VERSION 5.7 ;
BUSBITCHARS "[]" ;
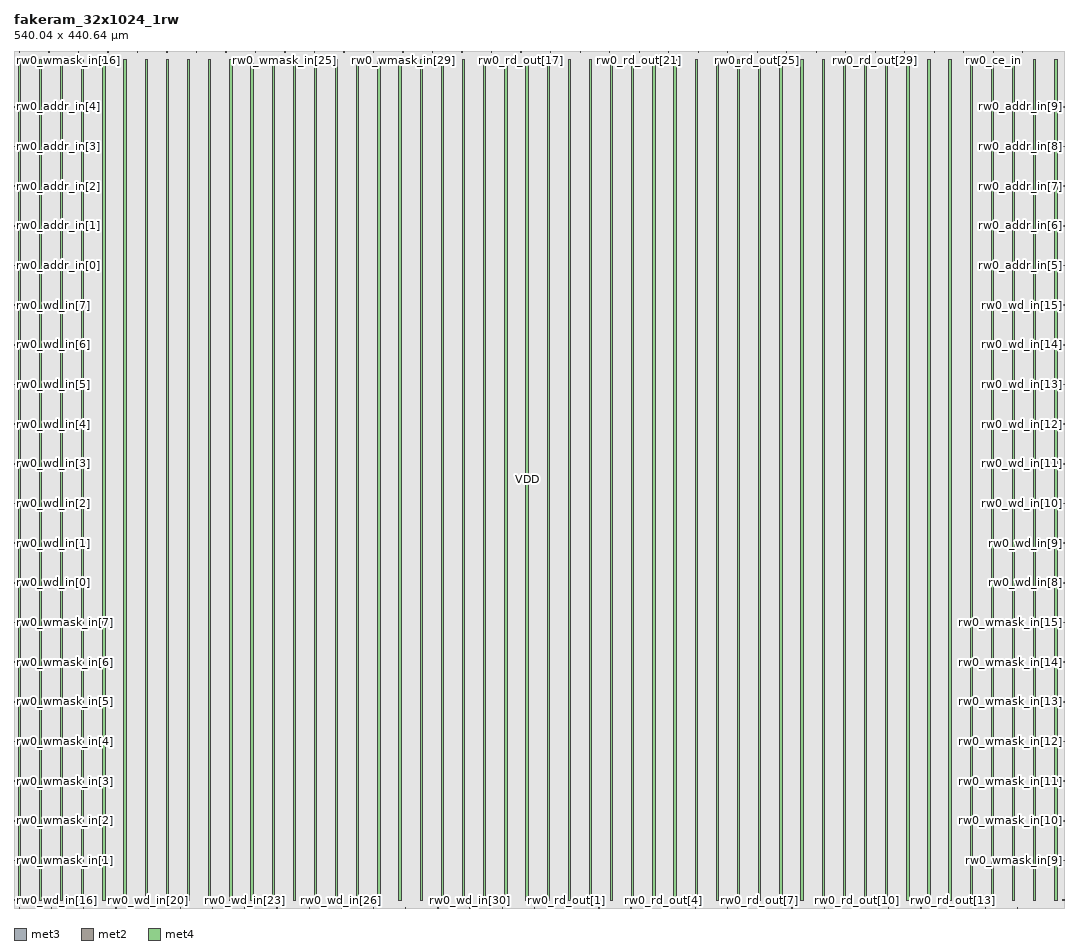
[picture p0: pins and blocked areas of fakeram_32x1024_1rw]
MACRO fakeram_32x1024_1rw
  FOREIGN fakeram_32x1024_1rw 0 0 ;
  SYMMETRY X Y R90 ;
  SIZE 540.040 BY 440.640 ;
  CLASS BLOCK ;
  PIN rw0_wmask_in[0]
    DIRECTION INPUT ;
    USE SIGNAL ;
    SHAPE ABUTMENT ;
    PORT
      LAYER met3 ;
      RECT 0.000 3.930 0.900 4.230 ;
    END
  END rw0_wmask_in[0]
  PIN rw0_wmask_in[1]
    DIRECTION INPUT ;
    USE SIGNAL ;
    SHAPE ABUTMENT ;
    PORT
      LAYER met3 ;
      RECT 0.000 24.330 0.900 24.630 ;
    END
  END rw0_wmask_in[1]
  PIN rw0_wmask_in[2]
    DIRECTION INPUT ;
    USE SIGNAL ;
    SHAPE ABUTMENT ;
    PORT
      LAYER met3 ;
      RECT 0.000 44.730 0.900 45.030 ;
    END
  END rw0_wmask_in[2]
  PIN rw0_wmask_in[3]
    DIRECTION INPUT ;
    USE SIGNAL ;
    SHAPE ABUTMENT ;
    PORT
      LAYER met3 ;
      RECT 0.000 65.130 0.900 65.430 ;
    END
  END rw0_wmask_in[3]
  PIN rw0_wmask_in[4]
    DIRECTION INPUT ;
    USE SIGNAL ;
    SHAPE ABUTMENT ;
    PORT
      LAYER met3 ;
      RECT 0.000 85.530 0.900 85.830 ;
    END
  END rw0_wmask_in[4]
  PIN rw0_wmask_in[5]
    DIRECTION INPUT ;
    USE SIGNAL ;
    SHAPE ABUTMENT ;
    PORT
      LAYER met3 ;
      RECT 0.000 105.930 0.900 106.230 ;
    END
  END rw0_wmask_in[5]
  PIN rw0_wmask_in[6]
    DIRECTION INPUT ;
    USE SIGNAL ;
    SHAPE ABUTMENT ;
    PORT
      LAYER met3 ;
      RECT 0.000 126.330 0.900 126.630 ;
    END
  END rw0_wmask_in[6]
  PIN rw0_wmask_in[7]
    DIRECTION INPUT ;
    USE SIGNAL ;
    SHAPE ABUTMENT ;
    PORT
      LAYER met3 ;
      RECT 0.000 146.730 0.900 147.030 ;
    END
  END rw0_wmask_in[7]
  PIN rw0_wmask_in[8]
    DIRECTION INPUT ;
    USE SIGNAL ;
    SHAPE ABUTMENT ;
    PORT
      LAYER met3 ;
      RECT 539.140 3.930 540.040 4.230 ;
    END
  END rw0_wmask_in[8]
  PIN rw0_wmask_in[9]
    DIRECTION INPUT ;
    USE SIGNAL ;
    SHAPE ABUTMENT ;
    PORT
      LAYER met3 ;
      RECT 539.140 24.330 540.040 24.630 ;
    END
  END rw0_wmask_in[9]
  PIN rw0_wmask_in[10]
    DIRECTION INPUT ;
    USE SIGNAL ;
    SHAPE ABUTMENT ;
    PORT
      LAYER met3 ;
      RECT 539.140 44.730 540.040 45.030 ;
    END
  END rw0_wmask_in[10]
  PIN rw0_wmask_in[11]
    DIRECTION INPUT ;
    USE SIGNAL ;
    SHAPE ABUTMENT ;
    PORT
      LAYER met3 ;
      RECT 539.140 65.130 540.040 65.430 ;
    END
  END rw0_wmask_in[11]
  PIN rw0_wmask_in[12]
    DIRECTION INPUT ;
    USE SIGNAL ;
    SHAPE ABUTMENT ;
    PORT
      LAYER met3 ;
      RECT 539.140 85.530 540.040 85.830 ;
    END
  END rw0_wmask_in[12]
  PIN rw0_wmask_in[13]
    DIRECTION INPUT ;
    USE SIGNAL ;
    SHAPE ABUTMENT ;
    PORT
      LAYER met3 ;
      RECT 539.140 105.930 540.040 106.230 ;
    END
  END rw0_wmask_in[13]
  PIN rw0_wmask_in[14]
    DIRECTION INPUT ;
    USE SIGNAL ;
    SHAPE ABUTMENT ;
    PORT
      LAYER met3 ;
      RECT 539.140 126.330 540.040 126.630 ;
    END
  END rw0_wmask_in[14]
  PIN rw0_wmask_in[15]
    DIRECTION INPUT ;
    USE SIGNAL ;
    SHAPE ABUTMENT ;
    PORT
      LAYER met3 ;
      RECT 539.140 146.730 540.040 147.030 ;
    END
  END rw0_wmask_in[15]
  PIN rw0_wmask_in[16]
    DIRECTION INPUT ;
    USE SIGNAL ;
    SHAPE ABUTMENT ;
    PORT
      LAYER met2 ;
      RECT 2.690 440.220 2.830 440.640 ;
    END
  END rw0_wmask_in[16]
  PIN rw0_wmask_in[17]
    DIRECTION INPUT ;
    USE SIGNAL ;
    SHAPE ABUTMENT ;
    PORT
      LAYER met2 ;
      RECT 17.870 440.220 18.010 440.640 ;
    END
  END rw0_wmask_in[17]
  PIN rw0_wmask_in[18]
    DIRECTION INPUT ;
    USE SIGNAL ;
    SHAPE ABUTMENT ;
    PORT
      LAYER met2 ;
      RECT 33.050 440.220 33.190 440.640 ;
    END
  END rw0_wmask_in[18]
  PIN rw0_wmask_in[19]
    DIRECTION INPUT ;
    USE SIGNAL ;
    SHAPE ABUTMENT ;
    PORT
      LAYER met2 ;
      RECT 48.230 440.220 48.370 440.640 ;
    END
  END rw0_wmask_in[19]
  PIN rw0_wmask_in[20]
    DIRECTION INPUT ;
    USE SIGNAL ;
    SHAPE ABUTMENT ;
    PORT
      LAYER met2 ;
      RECT 63.410 440.220 63.550 440.640 ;
    END
  END rw0_wmask_in[20]
  PIN rw0_wmask_in[21]
    DIRECTION INPUT ;
    USE SIGNAL ;
    SHAPE ABUTMENT ;
    PORT
      LAYER met2 ;
      RECT 78.590 440.220 78.730 440.640 ;
    END
  END rw0_wmask_in[21]
  PIN rw0_wmask_in[22]
    DIRECTION INPUT ;
    USE SIGNAL ;
    SHAPE ABUTMENT ;
    PORT
      LAYER met2 ;
      RECT 93.770 440.220 93.910 440.640 ;
    END
  END rw0_wmask_in[22]
  PIN rw0_wmask_in[23]
    DIRECTION INPUT ;
    USE SIGNAL ;
    SHAPE ABUTMENT ;
    PORT
      LAYER met2 ;
      RECT 108.950 440.220 109.090 440.640 ;
    END
  END rw0_wmask_in[23]
  PIN rw0_wmask_in[24]
    DIRECTION INPUT ;
    USE SIGNAL ;
    SHAPE ABUTMENT ;
    PORT
      LAYER met2 ;
      RECT 124.130 440.220 124.270 440.640 ;
    END
  END rw0_wmask_in[24]
  PIN rw0_wmask_in[25]
    DIRECTION INPUT ;
    USE SIGNAL ;
    SHAPE ABUTMENT ;
    PORT
      LAYER met2 ;
      RECT 139.310 440.220 139.450 440.640 ;
    END
  END rw0_wmask_in[25]
  PIN rw0_wmask_in[26]
    DIRECTION INPUT ;
    USE SIGNAL ;
    SHAPE ABUTMENT ;
    PORT
      LAYER met2 ;
      RECT 154.490 440.220 154.630 440.640 ;
    END
  END rw0_wmask_in[26]
  PIN rw0_wmask_in[27]
    DIRECTION INPUT ;
    USE SIGNAL ;
    SHAPE ABUTMENT ;
    PORT
      LAYER met2 ;
      RECT 169.670 440.220 169.810 440.640 ;
    END
  END rw0_wmask_in[27]
  PIN rw0_wmask_in[28]
    DIRECTION INPUT ;
    USE SIGNAL ;
    SHAPE ABUTMENT ;
    PORT
      LAYER met2 ;
      RECT 184.850 440.220 184.990 440.640 ;
    END
  END rw0_wmask_in[28]
  PIN rw0_wmask_in[29]
    DIRECTION INPUT ;
    USE SIGNAL ;
    SHAPE ABUTMENT ;
    PORT
      LAYER met2 ;
      RECT 200.030 440.220 200.170 440.640 ;
    END
  END rw0_wmask_in[29]
  PIN rw0_wmask_in[30]
    DIRECTION INPUT ;
    USE SIGNAL ;
    SHAPE ABUTMENT ;
    PORT
      LAYER met2 ;
      RECT 215.210 440.220 215.350 440.640 ;
    END
  END rw0_wmask_in[30]
  PIN rw0_wmask_in[31]
    DIRECTION INPUT ;
    USE SIGNAL ;
    SHAPE ABUTMENT ;
    PORT
      LAYER met2 ;
      RECT 230.390 440.220 230.530 440.640 ;
    END
  END rw0_wmask_in[31]
  PIN rw0_wd_in[0]
    DIRECTION INPUT ;
    USE SIGNAL ;
    SHAPE ABUTMENT ;
    PORT
      LAYER met3 ;
      RECT 0.000 167.130 0.900 167.430 ;
    END
  END rw0_wd_in[0]
  PIN rw0_wd_in[1]
    DIRECTION INPUT ;
    USE SIGNAL ;
    SHAPE ABUTMENT ;
    PORT
      LAYER met3 ;
      RECT 0.000 187.530 0.900 187.830 ;
    END
  END rw0_wd_in[1]
  PIN rw0_wd_in[2]
    DIRECTION INPUT ;
    USE SIGNAL ;
    SHAPE ABUTMENT ;
    PORT
      LAYER met3 ;
      RECT 0.000 207.930 0.900 208.230 ;
    END
  END rw0_wd_in[2]
  PIN rw0_wd_in[3]
    DIRECTION INPUT ;
    USE SIGNAL ;
    SHAPE ABUTMENT ;
    PORT
      LAYER met3 ;
      RECT 0.000 228.330 0.900 228.630 ;
    END
  END rw0_wd_in[3]
  PIN rw0_wd_in[4]
    DIRECTION INPUT ;
    USE SIGNAL ;
    SHAPE ABUTMENT ;
    PORT
      LAYER met3 ;
      RECT 0.000 248.730 0.900 249.030 ;
    END
  END rw0_wd_in[4]
  PIN rw0_wd_in[5]
    DIRECTION INPUT ;
    USE SIGNAL ;
    SHAPE ABUTMENT ;
    PORT
      LAYER met3 ;
      RECT 0.000 269.130 0.900 269.430 ;
    END
  END rw0_wd_in[5]
  PIN rw0_wd_in[6]
    DIRECTION INPUT ;
    USE SIGNAL ;
    SHAPE ABUTMENT ;
    PORT
      LAYER met3 ;
      RECT 0.000 289.530 0.900 289.830 ;
    END
  END rw0_wd_in[6]
  PIN rw0_wd_in[7]
    DIRECTION INPUT ;
    USE SIGNAL ;
    SHAPE ABUTMENT ;
    PORT
      LAYER met3 ;
      RECT 0.000 309.930 0.900 310.230 ;
    END
  END rw0_wd_in[7]
  PIN rw0_wd_in[8]
    DIRECTION INPUT ;
    USE SIGNAL ;
    SHAPE ABUTMENT ;
    PORT
      LAYER met3 ;
      RECT 539.140 167.130 540.040 167.430 ;
    END
  END rw0_wd_in[8]
  PIN rw0_wd_in[9]
    DIRECTION INPUT ;
    USE SIGNAL ;
    SHAPE ABUTMENT ;
    PORT
      LAYER met3 ;
      RECT 539.140 187.530 540.040 187.830 ;
    END
  END rw0_wd_in[9]
  PIN rw0_wd_in[10]
    DIRECTION INPUT ;
    USE SIGNAL ;
    SHAPE ABUTMENT ;
    PORT
      LAYER met3 ;
      RECT 539.140 207.930 540.040 208.230 ;
    END
  END rw0_wd_in[10]
  PIN rw0_wd_in[11]
    DIRECTION INPUT ;
    USE SIGNAL ;
    SHAPE ABUTMENT ;
    PORT
      LAYER met3 ;
      RECT 539.140 228.330 540.040 228.630 ;
    END
  END rw0_wd_in[11]
  PIN rw0_wd_in[12]
    DIRECTION INPUT ;
    USE SIGNAL ;
    SHAPE ABUTMENT ;
    PORT
      LAYER met3 ;
      RECT 539.140 248.730 540.040 249.030 ;
    END
  END rw0_wd_in[12]
  PIN rw0_wd_in[13]
    DIRECTION INPUT ;
    USE SIGNAL ;
    SHAPE ABUTMENT ;
    PORT
      LAYER met3 ;
      RECT 539.140 269.130 540.040 269.430 ;
    END
  END rw0_wd_in[13]
  PIN rw0_wd_in[14]
    DIRECTION INPUT ;
    USE SIGNAL ;
    SHAPE ABUTMENT ;
    PORT
      LAYER met3 ;
      RECT 539.140 289.530 540.040 289.830 ;
    END
  END rw0_wd_in[14]
  PIN rw0_wd_in[15]
    DIRECTION INPUT ;
    USE SIGNAL ;
    SHAPE ABUTMENT ;
    PORT
      LAYER met3 ;
      RECT 539.140 309.930 540.040 310.230 ;
    END
  END rw0_wd_in[15]
  PIN rw0_wd_in[16]
    DIRECTION OUTPUT ;
    USE SIGNAL ;
    SHAPE ABUTMENT ;
    PORT
      LAYER met2 ;
      RECT 2.690 0.000 2.830 0.420 ;
    END
  END rw0_wd_in[16]
  PIN rw0_wd_in[17]
    DIRECTION OUTPUT ;
    USE SIGNAL ;
    SHAPE ABUTMENT ;
    PORT
      LAYER met2 ;
      RECT 19.250 0.000 19.390 0.420 ;
    END
  END rw0_wd_in[17]
  PIN rw0_wd_in[18]
    DIRECTION OUTPUT ;
    USE SIGNAL ;
    SHAPE ABUTMENT ;
    PORT
      LAYER met2 ;
      RECT 35.810 0.000 35.950 0.420 ;
    END
  END rw0_wd_in[18]
  PIN rw0_wd_in[19]
    DIRECTION OUTPUT ;
    USE SIGNAL ;
    SHAPE ABUTMENT ;
    PORT
      LAYER met2 ;
      RECT 52.370 0.000 52.510 0.420 ;
    END
  END rw0_wd_in[19]
  PIN rw0_wd_in[20]
    DIRECTION OUTPUT ;
    USE SIGNAL ;
    SHAPE ABUTMENT ;
    PORT
      LAYER met2 ;
      RECT 68.930 0.000 69.070 0.420 ;
    END
  END rw0_wd_in[20]
  PIN rw0_wd_in[21]
    DIRECTION OUTPUT ;
    USE SIGNAL ;
    SHAPE ABUTMENT ;
    PORT
      LAYER met2 ;
      RECT 85.490 0.000 85.630 0.420 ;
    END
  END rw0_wd_in[21]
  PIN rw0_wd_in[22]
    DIRECTION OUTPUT ;
    USE SIGNAL ;
    SHAPE ABUTMENT ;
    PORT
      LAYER met2 ;
      RECT 102.050 0.000 102.190 0.420 ;
    END
  END rw0_wd_in[22]
  PIN rw0_wd_in[23]
    DIRECTION OUTPUT ;
    USE SIGNAL ;
    SHAPE ABUTMENT ;
    PORT
      LAYER met2 ;
      RECT 118.610 0.000 118.750 0.420 ;
    END
  END rw0_wd_in[23]
  PIN rw0_wd_in[24]
    DIRECTION OUTPUT ;
    USE SIGNAL ;
    SHAPE ABUTMENT ;
    PORT
      LAYER met2 ;
      RECT 135.170 0.000 135.310 0.420 ;
    END
  END rw0_wd_in[24]
  PIN rw0_wd_in[25]
    DIRECTION OUTPUT ;
    USE SIGNAL ;
    SHAPE ABUTMENT ;
    PORT
      LAYER met2 ;
      RECT 151.730 0.000 151.870 0.420 ;
    END
  END rw0_wd_in[25]
  PIN rw0_wd_in[26]
    DIRECTION OUTPUT ;
    USE SIGNAL ;
    SHAPE ABUTMENT ;
    PORT
      LAYER met2 ;
      RECT 168.290 0.000 168.430 0.420 ;
    END
  END rw0_wd_in[26]
  PIN rw0_wd_in[27]
    DIRECTION OUTPUT ;
    USE SIGNAL ;
    SHAPE ABUTMENT ;
    PORT
      LAYER met2 ;
      RECT 184.850 0.000 184.990 0.420 ;
    END
  END rw0_wd_in[27]
  PIN rw0_wd_in[28]
    DIRECTION OUTPUT ;
    USE SIGNAL ;
    SHAPE ABUTMENT ;
    PORT
      LAYER met2 ;
      RECT 201.410 0.000 201.550 0.420 ;
    END
  END rw0_wd_in[28]
  PIN rw0_wd_in[29]
    DIRECTION OUTPUT ;
    USE SIGNAL ;
    SHAPE ABUTMENT ;
    PORT
      LAYER met2 ;
      RECT 217.970 0.000 218.110 0.420 ;
    END
  END rw0_wd_in[29]
  PIN rw0_wd_in[30]
    DIRECTION OUTPUT ;
    USE SIGNAL ;
    SHAPE ABUTMENT ;
    PORT
      LAYER met2 ;
      RECT 234.530 0.000 234.670 0.420 ;
    END
  END rw0_wd_in[30]
  PIN rw0_wd_in[31]
    DIRECTION OUTPUT ;
    USE SIGNAL ;
    SHAPE ABUTMENT ;
    PORT
      LAYER met2 ;
      RECT 251.090 0.000 251.230 0.420 ;
    END
  END rw0_wd_in[31]
  PIN rw0_rd_out[0]
    DIRECTION OUTPUT ;
    USE SIGNAL ;
    SHAPE ABUTMENT ;
    PORT
      LAYER met2 ;
      RECT 267.650 0.000 267.790 0.420 ;
    END
  END rw0_rd_out[0]
  PIN rw0_rd_out[1]
    DIRECTION OUTPUT ;
    USE SIGNAL ;
    SHAPE ABUTMENT ;
    PORT
      LAYER met2 ;
      RECT 284.210 0.000 284.350 0.420 ;
    END
  END rw0_rd_out[1]
  PIN rw0_rd_out[2]
    DIRECTION OUTPUT ;
    USE SIGNAL ;
    SHAPE ABUTMENT ;
    PORT
      LAYER met2 ;
      RECT 300.770 0.000 300.910 0.420 ;
    END
  END rw0_rd_out[2]
  PIN rw0_rd_out[3]
    DIRECTION OUTPUT ;
    USE SIGNAL ;
    SHAPE ABUTMENT ;
    PORT
      LAYER met2 ;
      RECT 317.330 0.000 317.470 0.420 ;
    END
  END rw0_rd_out[3]
  PIN rw0_rd_out[4]
    DIRECTION OUTPUT ;
    USE SIGNAL ;
    SHAPE ABUTMENT ;
    PORT
      LAYER met2 ;
      RECT 333.890 0.000 334.030 0.420 ;
    END
  END rw0_rd_out[4]
  PIN rw0_rd_out[5]
    DIRECTION OUTPUT ;
    USE SIGNAL ;
    SHAPE ABUTMENT ;
    PORT
      LAYER met2 ;
      RECT 350.450 0.000 350.590 0.420 ;
    END
  END rw0_rd_out[5]
  PIN rw0_rd_out[6]
    DIRECTION OUTPUT ;
    USE SIGNAL ;
    SHAPE ABUTMENT ;
    PORT
      LAYER met2 ;
      RECT 367.010 0.000 367.150 0.420 ;
    END
  END rw0_rd_out[6]
  PIN rw0_rd_out[7]
    DIRECTION OUTPUT ;
    USE SIGNAL ;
    SHAPE ABUTMENT ;
    PORT
      LAYER met2 ;
      RECT 383.570 0.000 383.710 0.420 ;
    END
  END rw0_rd_out[7]
  PIN rw0_rd_out[8]
    DIRECTION OUTPUT ;
    USE SIGNAL ;
    SHAPE ABUTMENT ;
    PORT
      LAYER met2 ;
      RECT 400.130 0.000 400.270 0.420 ;
    END
  END rw0_rd_out[8]
  PIN rw0_rd_out[9]
    DIRECTION OUTPUT ;
    USE SIGNAL ;
    SHAPE ABUTMENT ;
    PORT
      LAYER met2 ;
      RECT 416.690 0.000 416.830 0.420 ;
    END
  END rw0_rd_out[9]
  PIN rw0_rd_out[10]
    DIRECTION OUTPUT ;
    USE SIGNAL ;
    SHAPE ABUTMENT ;
    PORT
      LAYER met2 ;
      RECT 433.250 0.000 433.390 0.420 ;
    END
  END rw0_rd_out[10]
  PIN rw0_rd_out[11]
    DIRECTION OUTPUT ;
    USE SIGNAL ;
    SHAPE ABUTMENT ;
    PORT
      LAYER met2 ;
      RECT 449.810 0.000 449.950 0.420 ;
    END
  END rw0_rd_out[11]
  PIN rw0_rd_out[12]
    DIRECTION OUTPUT ;
    USE SIGNAL ;
    SHAPE ABUTMENT ;
    PORT
      LAYER met2 ;
      RECT 466.370 0.000 466.510 0.420 ;
    END
  END rw0_rd_out[12]
  PIN rw0_rd_out[13]
    DIRECTION OUTPUT ;
    USE SIGNAL ;
    SHAPE ABUTMENT ;
    PORT
      LAYER met2 ;
      RECT 482.930 0.000 483.070 0.420 ;
    END
  END rw0_rd_out[13]
  PIN rw0_rd_out[14]
    DIRECTION OUTPUT ;
    USE SIGNAL ;
    SHAPE ABUTMENT ;
    PORT
      LAYER met2 ;
      RECT 499.490 0.000 499.630 0.420 ;
    END
  END rw0_rd_out[14]
  PIN rw0_rd_out[15]
    DIRECTION OUTPUT ;
    USE SIGNAL ;
    SHAPE ABUTMENT ;
    PORT
      LAYER met2 ;
      RECT 516.050 0.000 516.190 0.420 ;
    END
  END rw0_rd_out[15]
  PIN rw0_rd_out[16]
    DIRECTION OUTPUT ;
    USE SIGNAL ;
    SHAPE ABUTMENT ;
    PORT
      LAYER met2 ;
      RECT 245.570 440.220 245.710 440.640 ;
    END
  END rw0_rd_out[16]
  PIN rw0_rd_out[17]
    DIRECTION OUTPUT ;
    USE SIGNAL ;
    SHAPE ABUTMENT ;
    PORT
      LAYER met2 ;
      RECT 260.750 440.220 260.890 440.640 ;
    END
  END rw0_rd_out[17]
  PIN rw0_rd_out[18]
    DIRECTION OUTPUT ;
    USE SIGNAL ;
    SHAPE ABUTMENT ;
    PORT
      LAYER met2 ;
      RECT 275.930 440.220 276.070 440.640 ;
    END
  END rw0_rd_out[18]
  PIN rw0_rd_out[19]
    DIRECTION OUTPUT ;
    USE SIGNAL ;
    SHAPE ABUTMENT ;
    PORT
      LAYER met2 ;
      RECT 291.110 440.220 291.250 440.640 ;
    END
  END rw0_rd_out[19]
  PIN rw0_rd_out[20]
    DIRECTION OUTPUT ;
    USE SIGNAL ;
    SHAPE ABUTMENT ;
    PORT
      LAYER met2 ;
      RECT 306.290 440.220 306.430 440.640 ;
    END
  END rw0_rd_out[20]
  PIN rw0_rd_out[21]
    DIRECTION OUTPUT ;
    USE SIGNAL ;
    SHAPE ABUTMENT ;
    PORT
      LAYER met2 ;
      RECT 321.470 440.220 321.610 440.640 ;
    END
  END rw0_rd_out[21]
  PIN rw0_rd_out[22]
    DIRECTION OUTPUT ;
    USE SIGNAL ;
    SHAPE ABUTMENT ;
    PORT
      LAYER met2 ;
      RECT 336.650 440.220 336.790 440.640 ;
    END
  END rw0_rd_out[22]
  PIN rw0_rd_out[23]
    DIRECTION OUTPUT ;
    USE SIGNAL ;
    SHAPE ABUTMENT ;
    PORT
      LAYER met2 ;
      RECT 351.830 440.220 351.970 440.640 ;
    END
  END rw0_rd_out[23]
  PIN rw0_rd_out[24]
    DIRECTION OUTPUT ;
    USE SIGNAL ;
    SHAPE ABUTMENT ;
    PORT
      LAYER met2 ;
      RECT 367.010 440.220 367.150 440.640 ;
    END
  END rw0_rd_out[24]
  PIN rw0_rd_out[25]
    DIRECTION OUTPUT ;
    USE SIGNAL ;
    SHAPE ABUTMENT ;
    PORT
      LAYER met2 ;
      RECT 382.190 440.220 382.330 440.640 ;
    END
  END rw0_rd_out[25]
  PIN rw0_rd_out[26]
    DIRECTION OUTPUT ;
    USE SIGNAL ;
    SHAPE ABUTMENT ;
    PORT
      LAYER met2 ;
      RECT 397.370 440.220 397.510 440.640 ;
    END
  END rw0_rd_out[26]
  PIN rw0_rd_out[27]
    DIRECTION OUTPUT ;
    USE SIGNAL ;
    SHAPE ABUTMENT ;
    PORT
      LAYER met2 ;
      RECT 412.550 440.220 412.690 440.640 ;
    END
  END rw0_rd_out[27]
  PIN rw0_rd_out[28]
    DIRECTION OUTPUT ;
    USE SIGNAL ;
    SHAPE ABUTMENT ;
    PORT
      LAYER met2 ;
      RECT 427.730 440.220 427.870 440.640 ;
    END
  END rw0_rd_out[28]
  PIN rw0_rd_out[29]
    DIRECTION OUTPUT ;
    USE SIGNAL ;
    SHAPE ABUTMENT ;
    PORT
      LAYER met2 ;
      RECT 442.910 440.220 443.050 440.640 ;
    END
  END rw0_rd_out[29]
  PIN rw0_rd_out[30]
    DIRECTION OUTPUT ;
    USE SIGNAL ;
    SHAPE ABUTMENT ;
    PORT
      LAYER met2 ;
      RECT 458.090 440.220 458.230 440.640 ;
    END
  END rw0_rd_out[30]
  PIN rw0_rd_out[31]
    DIRECTION OUTPUT ;
    USE SIGNAL ;
    SHAPE ABUTMENT ;
    PORT
      LAYER met2 ;
      RECT 473.270 440.220 473.410 440.640 ;
    END
  END rw0_rd_out[31]
  PIN rw0_addr_in[0]
    DIRECTION INPUT ;
    USE SIGNAL ;
    SHAPE ABUTMENT ;
    PORT
      LAYER met3 ;
      RECT 0.000 330.330 0.900 330.630 ;
    END
  END rw0_addr_in[0]
  PIN rw0_addr_in[1]
    DIRECTION INPUT ;
    USE SIGNAL ;
    SHAPE ABUTMENT ;
    PORT
      LAYER met3 ;
      RECT 0.000 350.730 0.900 351.030 ;
    END
  END rw0_addr_in[1]
  PIN rw0_addr_in[2]
    DIRECTION INPUT ;
    USE SIGNAL ;
    SHAPE ABUTMENT ;
    PORT
      LAYER met3 ;
      RECT 0.000 371.130 0.900 371.430 ;
    END
  END rw0_addr_in[2]
  PIN rw0_addr_in[3]
    DIRECTION INPUT ;
    USE SIGNAL ;
    SHAPE ABUTMENT ;
    PORT
      LAYER met3 ;
      RECT 0.000 391.530 0.900 391.830 ;
    END
  END rw0_addr_in[3]
  PIN rw0_addr_in[4]
    DIRECTION INPUT ;
    USE SIGNAL ;
    SHAPE ABUTMENT ;
    PORT
      LAYER met3 ;
      RECT 0.000 411.930 0.900 412.230 ;
    END
  END rw0_addr_in[4]
  PIN rw0_addr_in[5]
    DIRECTION INPUT ;
    USE SIGNAL ;
    SHAPE ABUTMENT ;
    PORT
      LAYER met3 ;
      RECT 539.140 330.330 540.040 330.630 ;
    END
  END rw0_addr_in[5]
  PIN rw0_addr_in[6]
    DIRECTION INPUT ;
    USE SIGNAL ;
    SHAPE ABUTMENT ;
    PORT
      LAYER met3 ;
      RECT 539.140 350.730 540.040 351.030 ;
    END
  END rw0_addr_in[6]
  PIN rw0_addr_in[7]
    DIRECTION INPUT ;
    USE SIGNAL ;
    SHAPE ABUTMENT ;
    PORT
      LAYER met3 ;
      RECT 539.140 371.130 540.040 371.430 ;
    END
  END rw0_addr_in[7]
  PIN rw0_addr_in[8]
    DIRECTION INPUT ;
    USE SIGNAL ;
    SHAPE ABUTMENT ;
    PORT
      LAYER met3 ;
      RECT 539.140 391.530 540.040 391.830 ;
    END
  END rw0_addr_in[8]
  PIN rw0_addr_in[9]
    DIRECTION INPUT ;
    USE SIGNAL ;
    SHAPE ABUTMENT ;
    PORT
      LAYER met3 ;
      RECT 539.140 411.930 540.040 412.230 ;
    END
  END rw0_addr_in[9]
  PIN rw0_we_in
    DIRECTION INPUT ;
    USE SIGNAL ;
    SHAPE ABUTMENT ;
    PORT
      LAYER met2 ;
      RECT 488.450 440.220 488.590 440.640 ;
    END
  END rw0_we_in
  PIN rw0_ce_in
    DIRECTION INPUT ;
    USE SIGNAL ;
    SHAPE ABUTMENT ;
    PORT
      LAYER met2 ;
      RECT 503.630 440.220 503.770 440.640 ;
    END
  END rw0_ce_in
  PIN rw0_clk
    DIRECTION INPUT ;
    USE SIGNAL ;
    SHAPE ABUTMENT ;
    PORT
      LAYER met2 ;
      RECT 518.810 440.220 518.950 440.640 ;
    END
  END rw0_clk
  PIN VSS
    DIRECTION INOUT ;
    USE GROUND ;
    PORT
      LAYER met4 ;
      RECT 2.160 4.080 3.360 436.560 ;
      RECT 13.040 4.080 14.240 436.560 ;
      RECT 23.920 4.080 25.120 436.560 ;
      RECT 34.800 4.080 36.000 436.560 ;
      RECT 45.680 4.080 46.880 436.560 ;
      RECT 56.560 4.080 57.760 436.560 ;
      RECT 67.440 4.080 68.640 436.560 ;
      RECT 78.320 4.080 79.520 436.560 ;
      RECT 89.200 4.080 90.400 436.560 ;
      RECT 100.080 4.080 101.280 436.560 ;
      RECT 110.960 4.080 112.160 436.560 ;
      RECT 121.840 4.080 123.040 436.560 ;
      RECT 132.720 4.080 133.920 436.560 ;
      RECT 143.600 4.080 144.800 436.560 ;
      RECT 154.480 4.080 155.680 436.560 ;
      RECT 165.360 4.080 166.560 436.560 ;
      RECT 176.240 4.080 177.440 436.560 ;
      RECT 187.120 4.080 188.320 436.560 ;
      RECT 198.000 4.080 199.200 436.560 ;
      RECT 208.880 4.080 210.080 436.560 ;
      RECT 219.760 4.080 220.960 436.560 ;
      RECT 230.640 4.080 231.840 436.560 ;
      RECT 241.520 4.080 242.720 436.560 ;
      RECT 252.400 4.080 253.600 436.560 ;
      RECT 263.280 4.080 264.480 436.560 ;
      RECT 274.160 4.080 275.360 436.560 ;
      RECT 285.040 4.080 286.240 436.560 ;
      RECT 295.920 4.080 297.120 436.560 ;
      RECT 306.800 4.080 308.000 436.560 ;
      RECT 317.680 4.080 318.880 436.560 ;
      RECT 328.560 4.080 329.760 436.560 ;
      RECT 339.440 4.080 340.640 436.560 ;
      RECT 350.320 4.080 351.520 436.560 ;
      RECT 361.200 4.080 362.400 436.560 ;
      RECT 372.080 4.080 373.280 436.560 ;
      RECT 382.960 4.080 384.160 436.560 ;
      RECT 393.840 4.080 395.040 436.560 ;
      RECT 404.720 4.080 405.920 436.560 ;
      RECT 415.600 4.080 416.800 436.560 ;
      RECT 426.480 4.080 427.680 436.560 ;
      RECT 437.360 4.080 438.560 436.560 ;
      RECT 448.240 4.080 449.440 436.560 ;
      RECT 459.120 4.080 460.320 436.560 ;
      RECT 470.000 4.080 471.200 436.560 ;
      RECT 480.880 4.080 482.080 436.560 ;
      RECT 491.760 4.080 492.960 436.560 ;
      RECT 502.640 4.080 503.840 436.560 ;
      RECT 513.520 4.080 514.720 436.560 ;
      RECT 524.400 4.080 525.600 436.560 ;
      RECT 535.280 4.080 536.480 436.560 ;
    END
  END VSS
  PIN VDD
    DIRECTION INOUT ;
    USE POWER ;
    PORT
      LAYER met4 ;
      RECT 2.160 4.080 3.360 436.560 ;
      RECT 13.040 4.080 14.240 436.560 ;
      RECT 23.920 4.080 25.120 436.560 ;
      RECT 34.800 4.080 36.000 436.560 ;
      RECT 45.680 4.080 46.880 436.560 ;
      RECT 56.560 4.080 57.760 436.560 ;
      RECT 67.440 4.080 68.640 436.560 ;
      RECT 78.320 4.080 79.520 436.560 ;
      RECT 89.200 4.080 90.400 436.560 ;
      RECT 100.080 4.080 101.280 436.560 ;
      RECT 110.960 4.080 112.160 436.560 ;
      RECT 121.840 4.080 123.040 436.560 ;
      RECT 132.720 4.080 133.920 436.560 ;
      RECT 143.600 4.080 144.800 436.560 ;
      RECT 154.480 4.080 155.680 436.560 ;
      RECT 165.360 4.080 166.560 436.560 ;
      RECT 176.240 4.080 177.440 436.560 ;
      RECT 187.120 4.080 188.320 436.560 ;
      RECT 198.000 4.080 199.200 436.560 ;
      RECT 208.880 4.080 210.080 436.560 ;
      RECT 219.760 4.080 220.960 436.560 ;
      RECT 230.640 4.080 231.840 436.560 ;
      RECT 241.520 4.080 242.720 436.560 ;
      RECT 252.400 4.080 253.600 436.560 ;
      RECT 263.280 4.080 264.480 436.560 ;
      RECT 274.160 4.080 275.360 436.560 ;
      RECT 285.040 4.080 286.240 436.560 ;
      RECT 295.920 4.080 297.120 436.560 ;
      RECT 306.800 4.080 308.000 436.560 ;
      RECT 317.680 4.080 318.880 436.560 ;
      RECT 328.560 4.080 329.760 436.560 ;
      RECT 339.440 4.080 340.640 436.560 ;
      RECT 350.320 4.080 351.520 436.560 ;
      RECT 361.200 4.080 362.400 436.560 ;
      RECT 372.080 4.080 373.280 436.560 ;
      RECT 382.960 4.080 384.160 436.560 ;
      RECT 393.840 4.080 395.040 436.560 ;
      RECT 404.720 4.080 405.920 436.560 ;
      RECT 415.600 4.080 416.800 436.560 ;
      RECT 426.480 4.080 427.680 436.560 ;
      RECT 437.360 4.080 438.560 436.560 ;
      RECT 448.240 4.080 449.440 436.560 ;
      RECT 459.120 4.080 460.320 436.560 ;
      RECT 470.000 4.080 471.200 436.560 ;
      RECT 480.880 4.080 482.080 436.560 ;
      RECT 491.760 4.080 492.960 436.560 ;
      RECT 502.640 4.080 503.840 436.560 ;
      RECT 513.520 4.080 514.720 436.560 ;
      RECT 524.400 4.080 525.600 436.560 ;
      RECT 535.280 4.080 536.480 436.560 ;
    END
  END VDD
  OBS
    LAYER met1 ;
    RECT 0 0 540.040 440.640 ;
    LAYER met2 ;
    RECT 0 0 540.040 440.640 ;
    LAYER met3 ;
    RECT 0 0 540.040 440.640 ;
    LAYER met4 ;
    RECT 0 0 540.040 440.640 ;
  END
END fakeram_32x1024_1rw

END LIBRARY
